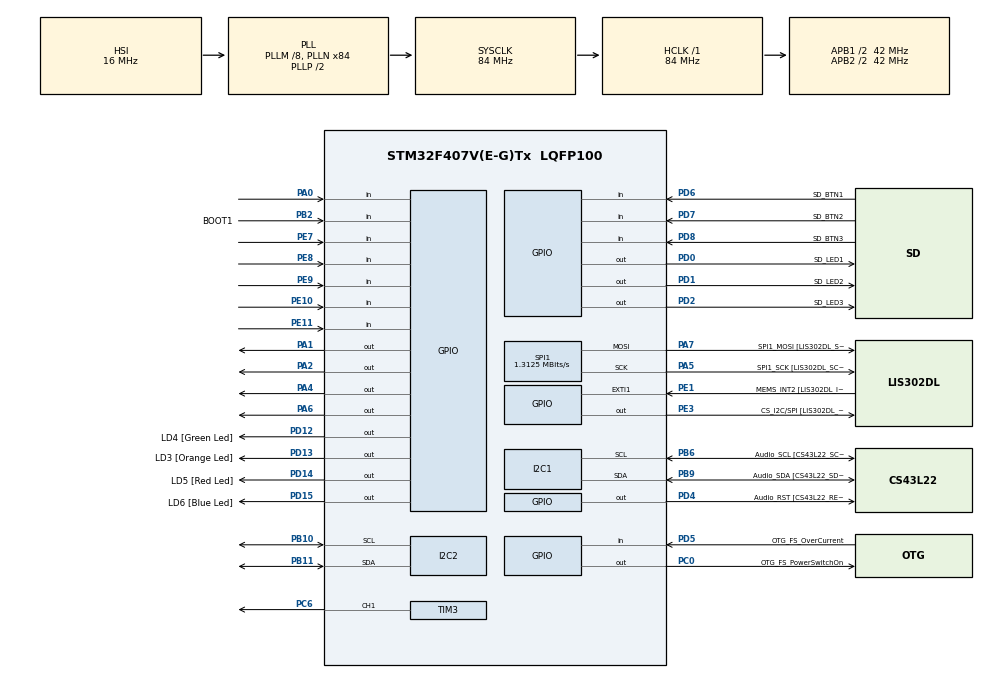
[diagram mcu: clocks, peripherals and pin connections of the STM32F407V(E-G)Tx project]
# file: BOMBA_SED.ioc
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ADC1.Channel-1\#ChannelRegularConversion=ADC_CHANNEL_TEMPSENSOR
ADC1.NbrOfConversionFlag=1
ADC1.Rank-1\#ChannelRegularConversion=1
ADC1.SamplingTime-1\#ChannelRegularConversion=ADC_SAMPLETIME_3CYCLES
ADC1.master=1
Mcu.Family=STM32F4
Mcu.Name=STM32F407V(E-G)Tx
Mcu.Package=LQFP100
NVIC.PriorityGroup=NVIC_PRIORITYGROUP_0
NVIC.TIM2_IRQn=true\:0\:0\:false\:false\:true\:true\:true\:true
PA0-WKUP.Signal=GPIO_Input
PA1.Signal=GPIO_Output
PA10.GPIO_Label=OTG_FS_ID
PA10.GPIO_Mode=GPIO_MODE_AF_PP
PA10.GPIO_PuPd=GPIO_NOPULL
PA10.GPIO_Speed=GPIO_SPEED_FREQ_LOW
PA10.Signal=USB_OTG_FS_ID
PA11.GPIO_Label=OTG_FS_DM
PA11.GPIO_Mode=GPIO_MODE_AF_PP
PA11.GPIO_PuPd=GPIO_NOPULL
PA11.GPIO_Speed=GPIO_SPEED_FREQ_LOW
PA11.Signal=USB_OTG_FS_DM
PA12.GPIO_Label=OTG_FS_DP
PA12.GPIO_Mode=GPIO_MODE_AF_PP
PA12.GPIO_PuPd=GPIO_NOPULL
PA12.GPIO_Speed=GPIO_SPEED_FREQ_LOW
PA12.Signal=USB_OTG_FS_DP
PA13.GPIO_Label=SWDIO
PA13.Signal=SYS_JTMS-SWDIO
PA14.GPIO_Label=SWCLK
PA14.Signal=SYS_JTCK-SWCLK
PA2.Signal=GPIO_Output
PA4.Signal=GPIO_Output
PA5.GPIO_Label=SPI1_SCK [LIS302DL_SCL/SPC]
PA5.GPIO_Mode=GPIO_MODE_AF_PP
PA5.GPIO_PuPd=GPIO_NOPULL
PA5.GPIO_Speed=GPIO_SPEED_FREQ_LOW
PA5.Mode=TX_Only_Simplex_Unidirect_Master
PA5.Signal=SPI1_SCK
PA6.Signal=GPIO_Output
PA7.GPIO_Label=SPI1_MOSI [LIS302DL_SDA/SDI/SDO]
PA7.GPIO_Mode=GPIO_MODE_AF_PP
PA7.GPIO_PuPd=GPIO_NOPULL
PA7.GPIO_Speed=GPIO_SPEED_FREQ_LOW
PA7.Mode=TX_Only_Simplex_Unidirect_Master
PA7.Signal=SPI1_MOSI
PA9.GPIO_Label=VBUS_FS
PA9.GPIO_Mode=GPIO_MODE_INPUT
PA9.GPIO_PuPd=GPIO_NOPULL
PA9.Signal=USB_OTG_FS_VBUS
PB10.Mode=I2C
PB10.Signal=I2C2_SCL
PB11.Mode=I2C
PB11.Signal=I2C2_SDA
PB2.GPIO_Label=BOOT1
PB2.GPIO_Mode=GPIO_MODE_INPUT
PB2.GPIO_PuPd=GPIO_NOPULL
PB2.Signal=GPIO_Input
PB3.GPIO_Label=SWO
PB3.Signal=SYS_JTDO-SWO
PB6.GPIO_Label=Audio_SCL [CS43L22_SCL]
PB6.GPIO_Mode=GPIO_MODE_AF_OD
PB6.GPIO_PuPd=GPIO_NOPULL
PB6.GPIO_Speed=GPIO_SPEED_FREQ_LOW
PB6.Mode=I2C
PB6.Signal=I2C1_SCL
PB9.GPIO_Label=Audio_SDA [CS43L22_SDA]
PB9.GPIO_Mode=GPIO_MODE_AF_OD
PB9.GPIO_PuPd=GPIO_NOPULL
PB9.GPIO_Speed=GPIO_SPEED_FREQ_LOW
PB9.Mode=I2C
PB9.Signal=I2C1_SDA
PC0.GPIO_Label=OTG_FS_PowerSwitchOn
PC0.GPIO_PuPd=GPIO_NOPULL
PC0.GPIO_Speed=GPIO_SPEED_FREQ_LOW
PC0.PinState=GPIO_PIN_SET
PC0.Signal=GPIO_Output
PC10.GPIO_Label=I2S3_SCK [CS43L22_SCLK]
PC10.GPIO_Mode=GPIO_MODE_AF_PP
PC10.GPIO_PuPd=GPIO_NOPULL
PC10.GPIO_Speed=GPIO_SPEED_FREQ_LOW
PC10.Signal=I2S3_CK
PC12.GPIO_Label=I2S3_SD [CS43L22_SDIN]
PC12.GPIO_Mode=GPIO_MODE_AF_PP
PC12.GPIO_PuPd=GPIO_NOPULL
PC12.GPIO_Speed=GPIO_SPEED_FREQ_LOW
PC12.Signal=I2S3_SD
PC14-OSC32_IN.GPIO_Label=PC14-OSC32_IN
PC14-OSC32_IN.Signal=RCC_OSC32_IN
PC15-OSC32_OUT.GPIO_Label=PC15-OSC32_OUT
PC15-OSC32_OUT.Signal=RCC_OSC32_OUT
PC3.GPIO_Label=PDM_OUT [MP45DT02_DOUT]
PC3.GPIO_Mode=GPIO_MODE_AF_PP
PC3.GPIO_PuPd=GPIO_NOPULL
PC3.GPIO_Speed=GPIO_SPEED_FREQ_LOW
PC3.Signal=I2S2_SD
PC6.Signal=S_TIM3_CH1
PC7.GPIO_Label=I2S3_MCK [CS43L22_MCLK]
PC7.GPIO_Mode=GPIO_MODE_AF_PP
PC7.GPIO_PuPd=GPIO_NOPULL
PC7.GPIO_Speed=GPIO_SPEED_FREQ_LOW
PC7.Signal=I2S3_MCK
PD0.GPIO_Label=SD_LED1
PD0.Signal=GPIO_Output
PD1.GPIO_Label=SD_LED2
PD1.Signal=GPIO_Output
PD12.GPIO_Label=LD4 [Green Led]
PD12.GPIO_PuPd=GPIO_NOPULL
PD12.GPIO_Speed=GPIO_SPEED_FREQ_LOW
PD12.Signal=GPIO_Output
PD13.GPIO_Label=LD3 [Orange Led]
PD13.GPIO_PuPd=GPIO_NOPULL
PD13.GPIO_Speed=GPIO_SPEED_FREQ_LOW
PD13.Signal=GPIO_Output
PD14.GPIO_Label=LD5 [Red Led]
PD14.GPIO_PuPd=GPIO_NOPULL
PD14.GPIO_Speed=GPIO_SPEED_FREQ_LOW
PD14.Signal=GPIO_Output
PD15.GPIO_Label=LD6 [Blue Led]
PD15.GPIO_PuPd=GPIO_NOPULL
PD15.GPIO_Speed=GPIO_SPEED_FREQ_LOW
PD15.Signal=GPIO_Output
PD2.GPIO_Label=SD_LED3
PD2.Signal=GPIO_Output
PD4.GPIO_Label=Audio_RST [CS43L22_RESET]
PD4.GPIO_PuPd=GPIO_NOPULL
PD4.GPIO_Speed=GPIO_SPEED_FREQ_LOW
PD4.Signal=GPIO_Output
PD5.GPIO_Label=OTG_FS_OverCurrent
PD5.GPIO_Mode=GPIO_MODE_INPUT
PD5.GPIO_PuPd=GPIO_NOPULL
PD5.Signal=GPIO_Input
PD6.GPIO_Label=SD_BTN1
PD6.GPIO_PuPd=GPIO_PULLUP
PD6.Signal=GPIO_Input
PD7.GPIO_Label=SD_BTN2
PD7.GPIO_PuPd=GPIO_PULLUP
PD7.Signal=GPIO_Input
PD8.GPIO_Label=SD_BTN3
PD8.GPIO_PuPd=GPIO_PULLUP
PD8.Signal=GPIO_Input
PE1.GPIO_Label=MEMS_INT2 [LIS302DL_INT2]
PE1.GPIO_ModeDefaultEXTI=GPIO_MODE_EVT_RISING
PE1.GPIO_PuPd=GPIO_NOPULL
PE1.Signal=GPXTI1
PE10.GPIO_PuPd=GPIO_PULLUP
PE10.Signal=GPIO_Input
PE11.GPIO_PuPd=GPIO_PULLUP
PE11.Signal=GPIO_Input
PE3.GPIO_Label=CS_I2C/SPI [LIS302DL_CS_I2C/SPI]
PE3.GPIO_PuPd=GPIO_NOPULL
PE3.GPIO_Speed=GPIO_SPEED_FREQ_LOW
PE3.Signal=GPIO_Output
PE7.GPIO_PuPd=GPIO_PULLUP
PE7.Signal=GPIO_Input
PE8.GPIO_PuPd=GPIO_PULLUP
PE8.Signal=GPIO_Input
PE9.GPIO_PuPd=GPIO_PULLUP
PE9.Signal=GPIO_Input
PH0-OSC_IN.GPIO_Label=PH0-OSC_IN
PH0-OSC_IN.Mode=HSE-External-Oscillator
PH0-OSC_IN.Signal=RCC_OSC_IN
PH1-OSC_OUT.GPIO_Label=PH1-OSC_OUT
PH1-OSC_OUT.Mode=HSE-External-Oscillator
PH1-OSC_OUT.Signal=RCC_OSC_OUT
ProjectManager.HeapSize=0x200
ProjectManager.StackSize=0x400
ProjectManager.TargetToolchain=STM32CubeIDE
RCC.48MHZClocksFreq_Value=24000000
RCC.AHBFreq_Value=84000000
RCC.APB1CLKDivider=RCC_HCLK_DIV2
RCC.APB1Freq_Value=42000000
RCC.APB1TimFreq_Value=84000000
RCC.APB2CLKDivider=RCC_HCLK_DIV2
RCC.APB2Freq_Value=42000000
RCC.APB2TimFreq_Value=84000000
RCC.CortexFreq_Value=84000000
RCC.HCLKFreq_Value=84000000
RCC.HSE_VALUE=8000000
RCC.HSI_VALUE=16000000
RCC.LSE_VALUE=32768
RCC.PLLM=8
RCC.PLLN=84
RCC.PLLQ=7
RCC.SYSCLKFreq_VALUE=84000000
RCC.SYSCLKSource=RCC_SYSCLKSOURCE_PLLCLK
RCC.VCOOutputFreq_Value=168000000
SH.S_TIM3_CH1.0=TIM3_CH1,PWM Generation1 CH1
SPI1.BaudRatePrescaler=SPI_BAUDRATEPRESCALER_32
SPI1.CalculateBaudRate=1.3125 MBits/s
SPI1.Direction=SPI_DIRECTION_2LINES
SPI1.Mode=SPI_MODE_MASTER
SPI1.VirtualType=VM_MASTER
TIM2.Period=3999
TIM2.Prescaler=41999
TIM3.Channel-PWM\ Generation1\ CH1=TIM_CHANNEL_1
TIM3.Period=1000 -1
TIM3.Prescaler=84-1
VP_ADC1_TempSens_Input.Mode=IN-TempSens
VP_TIM2_VS_ClockSourceINT.Mode=Internal
VP_TIM3_VS_ClockSourceINT.Mode=Internal
board=STM32F407G-DISC1

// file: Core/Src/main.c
/* USER CODE BEGIN Header */
/**
  ******************************************************************************
  * @file           : main.c
  * @brief          : Main program body
  ******************************************************************************
  * @attention
  *
  * Copyright (c) 2025 STMicroelectronics.
  * All rights reserved.
  *
  * This software is licensed under terms that can be found in the LICENSE file
  * in the root directory of this software component.
  * If no LICENSE file comes with this software, it is provided AS-IS.
  *
  ******************************************************************************
  */
/* USER CODE END Header */
#include "main.h"

/* USER CODE BEGIN Includes */
#include "lcd_i2c.h"
#include "game_master.h"
#include "sounds.h"
#include "simondice.h"
#include "airdef.h"
#include "safe.h"
#include "morse.h"
#include "ili9341.h"
#include "asteroids.h"
/* USER CODE END Includes */

ADC_HandleTypeDef hadc1;

I2C_HandleTypeDef hi2c1;
I2C_HandleTypeDef hi2c2;

SPI_HandleTypeDef hspi1;

TIM_HandleTypeDef htim2;
TIM_HandleTypeDef htim3;

/* USER CODE BEGIN PV */
extern GameContext bomb; // Importamos la variable global de la bomba para leer los estados
/* USER CODE END PV */

void SystemClock_Config(void);
static void MX_GPIO_Init(void);
static void MX_TIM2_Init(void);
static void MX_TIM3_Init(void);
static void MX_I2C2_Init(void);
static void MX_SPI1_Init(void);
static void MX_ADC1_Init(void);
static void MX_I2C1_Init(void);

/* USER CODE BEGIN 0 */
void HAL_GPIO_EXTI_Callback(uint16_t GPIO_Pin)
{

    //ZONA SIMON DICE
    if (GPIO_Pin == GPIO_PIN_6 || GPIO_Pin == GPIO_PIN_7 || GPIO_Pin == GPIO_PIN_8 ||
            GPIO_Pin == GPIO_PIN_9 || GPIO_Pin == GPIO_PIN_10 || GPIO_Pin == GPIO_PIN_11)
       {
           SimonDice_Boton_Handler(GPIO_Pin);
       }
}
/* USER CODE END 0 */

int main(void)
{

  /* MCU Configuration--------------------------------------------------------*/

  /* Reset of all peripherals, Initializes the Flash interface and the Systick. */
  HAL_Init();

  /* Configure the system clock */
  SystemClock_Config();

  /* Initialize all configured peripherals */
  MX_GPIO_Init();
  MX_TIM2_Init();
  MX_TIM3_Init();
  MX_I2C2_Init();
  MX_SPI1_Init();
  MX_ADC1_Init();
  MX_I2C1_Init();
  /* USER CODE BEGIN 2 */
  ILI9341_Init();
  SimonDice_Init();
  AirDef_Init();
  Safe_Init();
  Morse_Init();
  Asteroids_Init();

  GPIO_InitTypeDef GPIO_InitStruct = {0};
  __HAL_RCC_GPIOB_CLK_ENABLE(); // Encender reloj Puerto B
  __HAL_RCC_GPIOE_CLK_ENABLE(); // para los botones de activación de cara

  //CONFIGURAMOS LCD
  // Configuramos PB10 y PB11 con Pull-Up
  GPIO_InitStruct.Pin = GPIO_PIN_10 | GPIO_PIN_11;
  GPIO_InitStruct.Mode = GPIO_MODE_AF_OD;
  GPIO_InitStruct.Pull = GPIO_PULLUP;           // <--- LA CLAVE
  GPIO_InitStruct.Speed = GPIO_SPEED_FREQ_VERY_HIGH;
  GPIO_InitStruct.Alternate = GPIO_AF4_I2C2;
  HAL_GPIO_Init(GPIOB, &GPIO_InitStruct);

  // Configuración Botones de Activación de las Caras (PE7 - PE11)
  // Modo Input, con resistencia Pull-Up interna activada
  GPIO_InitStruct.Pin = GPIO_PIN_7|GPIO_PIN_8|GPIO_PIN_9|GPIO_PIN_10|GPIO_PIN_11;
  GPIO_InitStruct.Mode = GPIO_MODE_INPUT;
  GPIO_InitStruct.Pull = GPIO_PULLUP; // Botones conectados a tierra
  GPIO_InitStruct.Speed = GPIO_SPEED_FREQ_LOW;
  HAL_GPIO_Init(GPIOE, &GPIO_InitStruct);

  // Inicializar LCD
  LCD_Init();

  // Escribir mensaje
  LCD_SetCursor(0, 0); // Fila 0, Columna 0
  LCD_Print("PROYECTO MICROS");

  LCD_SetCursor(1, 0); // Fila 1, Columna 0
  LCD_Print("BOMBA ACTIVA");

  // Inicializar variables del juego
  Game_Init();

  /* USER CODE END 2 */

  /* Infinite loop */
  /* USER CODE BEGIN WHILE */
  while (1)
  {
	  // Llamar al cerebro del juego continuamente
	  Game_Update();

	  if (bomb.faceState[FACE_SIMON] == 1) {SimonDice_Loop();}
	  else if (bomb.faceState[FACE_AIRDEF] == 1){AirDef_Loop();}
	  else if (bomb.faceState[FACE_SAFE] == 1){Safe_Loop();}
	  else if (bomb.faceState[FACE_MORSE] == 1){Morse_Loop();}
	  else if (bomb.faceState[FACE_GYRO] == 1){Asteroids_Loop();}

    /* USER CODE END WHILE */

}

}

void SystemClock_Config(void)
{
  RCC_OscInitTypeDef RCC_OscInitStruct = {0};
  RCC_ClkInitTypeDef RCC_ClkInitStruct = {0};

  /** Configure the main internal regulator output voltage
  */
  __HAL_RCC_PWR_CLK_ENABLE();
  __HAL_PWR_VOLTAGESCALING_CONFIG(PWR_REGULATOR_VOLTAGE_SCALE1);

  /** Initializes the RCC Oscillators according to the specified parameters
  * in the RCC_OscInitTypeDef structure.
  */
  RCC_OscInitStruct.OscillatorType = RCC_OSCILLATORTYPE_HSI;
  RCC_OscInitStruct.HSIState = RCC_HSI_ON;
  RCC_OscInitStruct.HSICalibrationValue = RCC_HSICALIBRATION_DEFAULT;
  RCC_OscInitStruct.PLL.PLLState = RCC_PLL_ON;
  RCC_OscInitStruct.PLL.PLLSource = RCC_PLLSOURCE_HSI;
  RCC_OscInitStruct.PLL.PLLM = 8;
  RCC_OscInitStruct.PLL.PLLN = 84;
  RCC_OscInitStruct.PLL.PLLP = RCC_PLLP_DIV2;
  RCC_OscInitStruct.PLL.PLLQ = 7;
  if (HAL_RCC_OscConfig(&RCC_OscInitStruct) != HAL_OK)
  {
    Error_Handler();
  }

  /** Initializes the CPU, AHB and APB buses clocks
  */
  RCC_ClkInitStruct.ClockType = RCC_CLOCKTYPE_HCLK|RCC_CLOCKTYPE_SYSCLK
                              |RCC_CLOCKTYPE_PCLK1|RCC_CLOCKTYPE_PCLK2;
  RCC_ClkInitStruct.SYSCLKSource = RCC_SYSCLKSOURCE_PLLCLK;
  RCC_ClkInitStruct.AHBCLKDivider = RCC_SYSCLK_DIV1;
  RCC_ClkInitStruct.APB1CLKDivider = RCC_HCLK_DIV2;
  RCC_ClkInitStruct.APB2CLKDivider = RCC_HCLK_DIV2;

  if (HAL_RCC_ClockConfig(&RCC_ClkInitStruct, FLASH_LATENCY_2) != HAL_OK)
  {
    Error_Handler();
  }
}

static void MX_ADC1_Init(void)
{

  ADC_ChannelConfTypeDef sConfig = {0};

  /** Configure the global features of the ADC (Clock, Resolution, Data Alignment and number of conversion)
  */
  hadc1.Instance = ADC1;
  hadc1.Init.ClockPrescaler = ADC_CLOCK_SYNC_PCLK_DIV2;
  hadc1.Init.Resolution = ADC_RESOLUTION_12B;
  hadc1.Init.ScanConvMode = DISABLE;
  hadc1.Init.ContinuousConvMode = DISABLE;
  hadc1.Init.DiscontinuousConvMode = DISABLE;
  hadc1.Init.ExternalTrigConvEdge = ADC_EXTERNALTRIGCONVEDGE_NONE;
  hadc1.Init.ExternalTrigConv = ADC_SOFTWARE_START;
  hadc1.Init.DataAlign = ADC_DATAALIGN_RIGHT;
  hadc1.Init.NbrOfConversion = 1;
  hadc1.Init.DMAContinuousRequests = DISABLE;
  hadc1.Init.EOCSelection = ADC_EOC_SINGLE_CONV;
  if (HAL_ADC_Init(&hadc1) != HAL_OK)
  {
    Error_Handler();
  }

  /** Configure for the selected ADC regular channel its corresponding rank in the sequencer and its sample time.
  */
  sConfig.Channel = ADC_CHANNEL_TEMPSENSOR;
  sConfig.Rank = 1;
  sConfig.SamplingTime = ADC_SAMPLETIME_3CYCLES;
  if (HAL_ADC_ConfigChannel(&hadc1, &sConfig) != HAL_OK)
  {
    Error_Handler();
  }

}

static void MX_I2C1_Init(void)
{

  hi2c1.Instance = I2C1;
  hi2c1.Init.ClockSpeed = 100000;
  hi2c1.Init.DutyCycle = I2C_DUTYCYCLE_2;
  hi2c1.Init.OwnAddress1 = 0;
  hi2c1.Init.AddressingMode = I2C_ADDRESSINGMODE_7BIT;
  hi2c1.Init.DualAddressMode = I2C_DUALADDRESS_DISABLE;
  hi2c1.Init.OwnAddress2 = 0;
  hi2c1.Init.GeneralCallMode = I2C_GENERALCALL_DISABLE;
  hi2c1.Init.NoStretchMode = I2C_NOSTRETCH_DISABLE;
  if (HAL_I2C_Init(&hi2c1) != HAL_OK)
  {
    Error_Handler();
  }

}

static void MX_I2C2_Init(void)
{

  hi2c2.Instance = I2C2;
  hi2c2.Init.ClockSpeed = 100000;
  hi2c2.Init.DutyCycle = I2C_DUTYCYCLE_2;
  hi2c2.Init.OwnAddress1 = 0;
  hi2c2.Init.AddressingMode = I2C_ADDRESSINGMODE_7BIT;
  hi2c2.Init.DualAddressMode = I2C_DUALADDRESS_DISABLE;
  hi2c2.Init.OwnAddress2 = 0;
  hi2c2.Init.GeneralCallMode = I2C_GENERALCALL_DISABLE;
  hi2c2.Init.NoStretchMode = I2C_NOSTRETCH_DISABLE;
  if (HAL_I2C_Init(&hi2c2) != HAL_OK)
  {
    Error_Handler();
  }

}

static void MX_SPI1_Init(void)
{

  /* SPI1 parameter configuration*/
  hspi1.Instance = SPI1;
  hspi1.Init.Mode = SPI_MODE_MASTER;
  hspi1.Init.Direction = SPI_DIRECTION_2LINES;
  hspi1.Init.DataSize = SPI_DATASIZE_8BIT;
  hspi1.Init.CLKPolarity = SPI_POLARITY_LOW;
  hspi1.Init.CLKPhase = SPI_PHASE_1EDGE;
  hspi1.Init.NSS = SPI_NSS_SOFT;
  hspi1.Init.BaudRatePrescaler = SPI_BAUDRATEPRESCALER_8;
  hspi1.Init.FirstBit = SPI_FIRSTBIT_MSB;
  hspi1.Init.TIMode = SPI_TIMODE_DISABLE;
  hspi1.Init.CRCCalculation = SPI_CRCCALCULATION_DISABLE;
  hspi1.Init.CRCPolynomial = 10;
  if (HAL_SPI_Init(&hspi1) != HAL_OK)
  {
    Error_Handler();
  }

}

static void MX_TIM2_Init(void)
{

  TIM_ClockConfigTypeDef sClockSourceConfig = {0};
  TIM_MasterConfigTypeDef sMasterConfig = {0};

  htim2.Instance = TIM2;
  htim2.Init.Prescaler = 41999;
  htim2.Init.CounterMode = TIM_COUNTERMODE_UP;
  htim2.Init.Period = 3999;
  htim2.Init.ClockDivision = TIM_CLOCKDIVISION_DIV1;
  htim2.Init.AutoReloadPreload = TIM_AUTORELOAD_PRELOAD_DISABLE;
  if (HAL_TIM_Base_Init(&htim2) != HAL_OK)
  {
    Error_Handler();
  }
  sClockSourceConfig.ClockSource = TIM_CLOCKSOURCE_INTERNAL;
  if (HAL_TIM_ConfigClockSource(&htim2, &sClockSourceConfig) != HAL_OK)
  {
    Error_Handler();
  }
  sMasterConfig.MasterOutputTrigger = TIM_TRGO_RESET;
  sMasterConfig.MasterSlaveMode = TIM_MASTERSLAVEMODE_DISABLE;
  if (HAL_TIMEx_MasterConfigSynchronization(&htim2, &sMasterConfig) != HAL_OK)
  {
    Error_Handler();
  }

}

static void MX_TIM3_Init(void)
{

  TIM_ClockConfigTypeDef sClockSourceConfig = {0};
  TIM_MasterConfigTypeDef sMasterConfig = {0};
  TIM_OC_InitTypeDef sConfigOC = {0};

  htim3.Instance = TIM3;
  htim3.Init.Prescaler = 84-1;
  htim3.Init.CounterMode = TIM_COUNTERMODE_UP;
  htim3.Init.Period = 1000 -1;
  htim3.Init.ClockDivision = TIM_CLOCKDIVISION_DIV1;
  htim3.Init.AutoReloadPreload = TIM_AUTORELOAD_PRELOAD_DISABLE;
  if (HAL_TIM_Base_Init(&htim3) != HAL_OK)
  {
    Error_Handler();
  }
  sClockSourceConfig.ClockSource = TIM_CLOCKSOURCE_INTERNAL;
  if (HAL_TIM_ConfigClockSource(&htim3, &sClockSourceConfig) != HAL_OK)
  {
    Error_Handler();
  }
  if (HAL_TIM_PWM_Init(&htim3) != HAL_OK)
  {
    Error_Handler();
  }
  sMasterConfig.MasterOutputTrigger = TIM_TRGO_RESET;
  sMasterConfig.MasterSlaveMode = TIM_MASTERSLAVEMODE_DISABLE;
  if (HAL_TIMEx_MasterConfigSynchronization(&htim3, &sMasterConfig) != HAL_OK)
  {
    Error_Handler();
  }
  sConfigOC.OCMode = TIM_OCMODE_PWM1;
  sConfigOC.Pulse = 0;
  sConfigOC.OCPolarity = TIM_OCPOLARITY_HIGH;
  sConfigOC.OCFastMode = TIM_OCFAST_DISABLE;
  if (HAL_TIM_PWM_ConfigChannel(&htim3, &sConfigOC, TIM_CHANNEL_1) != HAL_OK)
  {
    Error_Handler();
  }
  HAL_TIM_MspPostInit(&htim3);

}

static void MX_GPIO_Init(void)
{
  GPIO_InitTypeDef GPIO_InitStruct = {0};

  /* GPIO Ports Clock Enable */
  __HAL_RCC_GPIOE_CLK_ENABLE();
  __HAL_RCC_GPIOC_CLK_ENABLE();
  __HAL_RCC_GPIOH_CLK_ENABLE();
  __HAL_RCC_GPIOA_CLK_ENABLE();
  __HAL_RCC_GPIOB_CLK_ENABLE();
  __HAL_RCC_GPIOD_CLK_ENABLE();

  // Poner niveles iniciales seguros (CS y RST altos = inactivos)
    HAL_GPIO_WritePin(GPIOA, GPIO_PIN_8, GPIO_PIN_SET);
    HAL_GPIO_WritePin(GPIOC, GPIO_PIN_8, GPIO_PIN_SET);
    HAL_GPIO_WritePin(GPIOC, GPIO_PIN_9, GPIO_PIN_RESET);

    // PA8 -> CS
    GPIO_InitStruct.Pin = GPIO_PIN_8;
    GPIO_InitStruct.Mode = GPIO_MODE_OUTPUT_PP;
    GPIO_InitStruct.Pull = GPIO_NOPULL;
    GPIO_InitStruct.Speed = GPIO_SPEED_FREQ_VERY_HIGH;
    HAL_GPIO_Init(GPIOA, &GPIO_InitStruct);

    // PC8 -> RES, PC9 -> DC
    GPIO_InitStruct.Pin = GPIO_PIN_8|GPIO_PIN_9;
    HAL_GPIO_Init(GPIOC, &GPIO_InitStruct);

  /*Configure GPIO pin Output Level */
  HAL_GPIO_WritePin(CS_I2C_SPI_GPIO_Port, CS_I2C_SPI_Pin, GPIO_PIN_RESET);

  /*Configure GPIO pin Output Level */
  HAL_GPIO_WritePin(OTG_FS_PowerSwitchOn_GPIO_Port, OTG_FS_PowerSwitchOn_Pin, GPIO_PIN_SET);

  /*Configure GPIO pin Output Level */
  HAL_GPIO_WritePin(GPIOA, GPIO_PIN_1|GPIO_PIN_2|GPIO_PIN_4, GPIO_PIN_RESET);

  /*Configure GPIO pin Output Level */
  HAL_GPIO_WritePin(GPIOD, LD4_Pin|LD3_Pin|LD5_Pin|LD6_Pin
                          |SD_LED1_Pin|SD_LED2_Pin|SD_LED3_Pin|Audio_RST_Pin, GPIO_PIN_RESET);

  /*Configure GPIO pin : CS_I2C_SPI_Pin */
  GPIO_InitStruct.Pin = CS_I2C_SPI_Pin;
  GPIO_InitStruct.Mode = GPIO_MODE_OUTPUT_PP;
  GPIO_InitStruct.Pull = GPIO_NOPULL;
  GPIO_InitStruct.Speed = GPIO_SPEED_FREQ_LOW;
  HAL_GPIO_Init(CS_I2C_SPI_GPIO_Port, &GPIO_InitStruct);

  /*Configure GPIO pin : OTG_FS_PowerSwitchOn_Pin */
  GPIO_InitStruct.Pin = OTG_FS_PowerSwitchOn_Pin;
  GPIO_InitStruct.Mode = GPIO_MODE_OUTPUT_PP;
  GPIO_InitStruct.Pull = GPIO_NOPULL;
  GPIO_InitStruct.Speed = GPIO_SPEED_FREQ_LOW;
  HAL_GPIO_Init(OTG_FS_PowerSwitchOn_GPIO_Port, &GPIO_InitStruct);

  /*Configure GPIO pin : PDM_OUT_Pin */
  GPIO_InitStruct.Pin = PDM_OUT_Pin;
  GPIO_InitStruct.Mode = GPIO_MODE_AF_PP;
  GPIO_InitStruct.Pull = GPIO_NOPULL;
  GPIO_InitStruct.Speed = GPIO_SPEED_FREQ_LOW;
  GPIO_InitStruct.Alternate = GPIO_AF5_SPI2;
  HAL_GPIO_Init(PDM_OUT_GPIO_Port, &GPIO_InitStruct);

  /*Configure GPIO pin : PA0 */
  GPIO_InitStruct.Pin = GPIO_PIN_0;
  GPIO_InitStruct.Mode = GPIO_MODE_INPUT;
  GPIO_InitStruct.Pull = GPIO_NOPULL;
  HAL_GPIO_Init(GPIOA, &GPIO_InitStruct);

  /*Configure GPIO pins : PA1 PA2 PA4 PA6 */
  GPIO_InitStruct.Pin = GPIO_PIN_1|GPIO_PIN_2|GPIO_PIN_4|GPIO_PIN_6;
  GPIO_InitStruct.Mode = GPIO_MODE_OUTPUT_PP;
  GPIO_InitStruct.Pull = GPIO_NOPULL;
  GPIO_InitStruct.Speed = GPIO_SPEED_FREQ_LOW;
  HAL_GPIO_Init(GPIOA, &GPIO_InitStruct);

  /*Configure GPIO pin : BOOT1_Pin */
  GPIO_InitStruct.Pin = BOOT1_Pin;
  GPIO_InitStruct.Mode = GPIO_MODE_INPUT;
  GPIO_InitStruct.Pull = GPIO_NOPULL;
  HAL_GPIO_Init(BOOT1_GPIO_Port, &GPIO_InitStruct);

  /*Configure GPIO pins : PE7 PE8 PE9 PE10
                           PE11 */
  GPIO_InitStruct.Pin = GPIO_PIN_7|GPIO_PIN_8|GPIO_PIN_9|GPIO_PIN_10
                          |GPIO_PIN_11;
  GPIO_InitStruct.Mode = GPIO_MODE_INPUT;
  GPIO_InitStruct.Pull = GPIO_PULLUP;
  HAL_GPIO_Init(GPIOE, &GPIO_InitStruct);

  /*Configure GPIO pins : SD_BTN3_Pin SD_BTN1_Pin SD_BTN2_Pin */
  GPIO_InitStruct.Pin = SD_BTN3_Pin|SD_BTN1_Pin|SD_BTN2_Pin;
  GPIO_InitStruct.Mode = GPIO_MODE_INPUT;
  GPIO_InitStruct.Pull = GPIO_PULLUP;
  HAL_GPIO_Init(GPIOD, &GPIO_InitStruct);

  /*Configure GPIO pins : LD4_Pin LD3_Pin LD5_Pin LD6_Pin
                           SD_LED1_Pin SD_LED2_Pin SD_LED3_Pin Audio_RST_Pin */
  GPIO_InitStruct.Pin = LD4_Pin|LD3_Pin|LD5_Pin|LD6_Pin
                          |SD_LED1_Pin|SD_LED2_Pin|SD_LED3_Pin|Audio_RST_Pin;
  GPIO_InitStruct.Mode = GPIO_MODE_OUTPUT_PP;
  GPIO_InitStruct.Pull = GPIO_NOPULL;
  GPIO_InitStruct.Speed = GPIO_SPEED_FREQ_LOW;
  HAL_GPIO_Init(GPIOD, &GPIO_InitStruct);

  /*Configure GPIO pins : I2S3_MCK_Pin I2S3_SCK_Pin I2S3_SD_Pin */
  GPIO_InitStruct.Pin = I2S3_MCK_Pin|I2S3_SCK_Pin|I2S3_SD_Pin;
  GPIO_InitStruct.Mode = GPIO_MODE_AF_PP;
  GPIO_InitStruct.Pull = GPIO_NOPULL;
  GPIO_InitStruct.Speed = GPIO_SPEED_FREQ_LOW;
  GPIO_InitStruct.Alternate = GPIO_AF6_SPI3;
  HAL_GPIO_Init(GPIOC, &GPIO_InitStruct);

  /*Configure GPIO pin : VBUS_FS_Pin */
  GPIO_InitStruct.Pin = VBUS_FS_Pin;
  GPIO_InitStruct.Mode = GPIO_MODE_INPUT;
  GPIO_InitStruct.Pull = GPIO_NOPULL;
  HAL_GPIO_Init(VBUS_FS_GPIO_Port, &GPIO_InitStruct);

  /*Configure GPIO pins : OTG_FS_ID_Pin OTG_FS_DM_Pin OTG_FS_DP_Pin */
  GPIO_InitStruct.Pin = OTG_FS_ID_Pin|OTG_FS_DM_Pin|OTG_FS_DP_Pin;
  GPIO_InitStruct.Mode = GPIO_MODE_AF_PP;
  GPIO_InitStruct.Pull = GPIO_NOPULL;
  GPIO_InitStruct.Speed = GPIO_SPEED_FREQ_LOW;
  GPIO_InitStruct.Alternate = GPIO_AF10_OTG_FS;
  HAL_GPIO_Init(GPIOA, &GPIO_InitStruct);

  /*Configure GPIO pin : OTG_FS_OverCurrent_Pin */
  GPIO_InitStruct.Pin = OTG_FS_OverCurrent_Pin;
  GPIO_InitStruct.Mode = GPIO_MODE_INPUT;
  GPIO_InitStruct.Pull = GPIO_NOPULL;
  HAL_GPIO_Init(OTG_FS_OverCurrent_GPIO_Port, &GPIO_InitStruct);

  /*Configure GPIO pin : MEMS_INT2_Pin */
  GPIO_InitStruct.Pin = MEMS_INT2_Pin;
  GPIO_InitStruct.Mode = GPIO_MODE_EVT_RISING;
  GPIO_InitStruct.Pull = GPIO_NOPULL;
  HAL_GPIO_Init(MEMS_INT2_GPIO_Port, &GPIO_InitStruct);

  /* BUZZER PIN PA4 */
    HAL_GPIO_WritePin(GPIOA, GPIO_PIN_4, GPIO_PIN_RESET);
    GPIO_InitStruct.Pin = GPIO_PIN_4; // <--- AQUÍ ESTÁ EL CAMBIO CLAVE
    GPIO_InitStruct.Mode = GPIO_MODE_OUTPUT_PP;
    GPIO_InitStruct.Pull = GPIO_NOPULL;
    GPIO_InitStruct.Speed = GPIO_SPEED_FREQ_LOW;
    HAL_GPIO_Init(GPIOA, &GPIO_InitStruct);

}

/* USER CODE BEGIN 4 */

// Interrupción del Timer 2 (Salta cada 1 segundo)
void HAL_TIM_PeriodElapsedCallback(TIM_HandleTypeDef *htim) {
    if (htim->Instance == TIM2) {
        Game_TimerTick(); // Llamamos a nuestra lógica de tiempo
    }
}

/* USER CODE END 4 */

void Error_Handler(void)
{
  __disable_irq();
  while (1)
  {
  }
}
